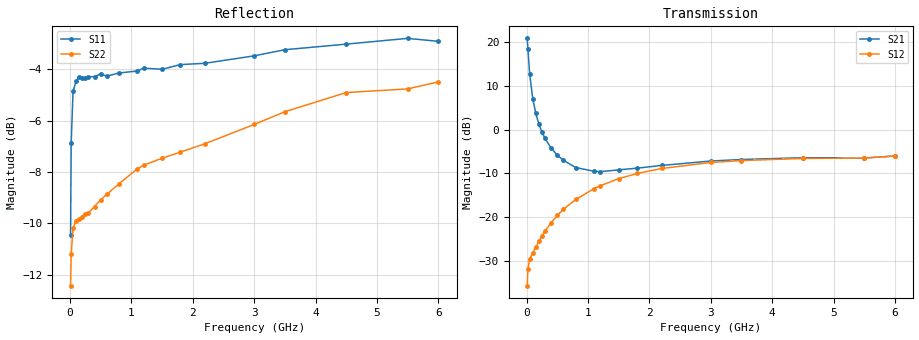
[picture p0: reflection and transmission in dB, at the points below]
! Infineon Technologies  Discrete & RF Semiconductors
! BF775
! Si NPN RF Bipolar Junction Transistor in SOT23
! VCE = 0.5 V  IC = 30 mA
! Common Emitter S-Parameters:  May  1996
# GHz  S  MA  R  50
!  f  S11  S21  S12  S22
! GHz  MAG  ANG  MAG  ANG  MAG  ANG  MAG  ANG
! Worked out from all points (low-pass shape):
!   36 points, 10 MHz to 6 GHz, reference 50 ohm
!   highest |S21| = 20.90 dB at 10 MHz (marker M1); lowest = -9.6 dB at 1.2 GHz (marker M2)
!   |S21| within 3 dB of the highest: start of sweep to 23.32 MHz
!   lowest |S11| = -10.4 dB at 10 MHz (marker M3), VSWR 1.86, Z = 35.6 - j22.4 ohm
!   |S11| at or under -10 dB: start of sweep to 11.21 MHz
!   |S22| runs from -12.4 to -4.5 dB; largest |S21 - S12| = 11
!   S11 on the Smith chart (normalised r, x): 10 MHz: 0.71, -0.45; 50 MHz: 0.28, -0.16; 500 MHz: 0.24, +0.13; 1.5 GHz: 0.28, +0.46; 3 GHz: 0.38, +0.93; 6 GHz: 0.66, +1.64
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0.01  0.3009 -108.2  11.1 150.1  0.0164 55.3  0.2392 -72.0
0.02  0.4531 -133.6  8.47 130.5  0.0255 43.2  0.2752 -109.4
0.05  0.5716 -159.8  4.296 106.1  0.0332 34.2  0.3096 -147.7
0.1  0.5982 -172.8  2.25 92.5  0.0386 38.3  0.3202 -164.0
0.15  0.6107 -178.1  1.533 85.0  0.0453 44.3  0.3228 -169.6
0.2  0.607 177.9  1.159 79.3  0.0526 49.7  0.3262 -172.8
0.25  0.6068 175.1  0.937 74.7  0.0606 53.2  0.3305 -175.1
0.3  0.6104 172.5  0.794 71.2  0.0691 56.3  0.3317 -176.4
0.4  0.611 167.7  0.615 63.7  0.0865 59.6  0.3411 -179.1
0.5  0.618 164.4  0.511 58.5  0.1045 60.6  0.3516 178.2
0.6  0.6122 160.0  0.446 53.8  0.1231 60.7  0.3603 175.6
0.8  0.621 152.7  0.369 48.2  0.1592 59.3  0.3778 170.3
1.1  0.6264 141.2  0.334 44.0  0.2121 55.0  0.4043 161.3
1.2  0.6346 137.4  0.331 43.3  0.2285 53.2  0.4106 158.2
1.5  0.6314 127.8  0.347 40.3  0.2752 47.5  0.4236 149.7
1.8  0.6447 118.4  0.363 37.2  0.3154 41.6  0.4355 141.1
2.2  0.6485 107.6  0.39 31.3  0.3599 34.2  0.4521 131.2
3  0.6705 89.6  0.438 18.6  0.4214 20.3  0.4929 114.4
3.5  0.6892 81.8  0.456 11.9  0.4433 12.9  0.5218 106.3
4.5  0.7067 69.7  0.478 0.5  0.469 1.0  0.5688 93.5
5.5  0.7252 61.1  0.475 -9.4  0.4736 -9.2  0.5781 81.2
6  0.7156 57.1  0.5 -11.9  0.4997 -12.5  0.5966 82.6
